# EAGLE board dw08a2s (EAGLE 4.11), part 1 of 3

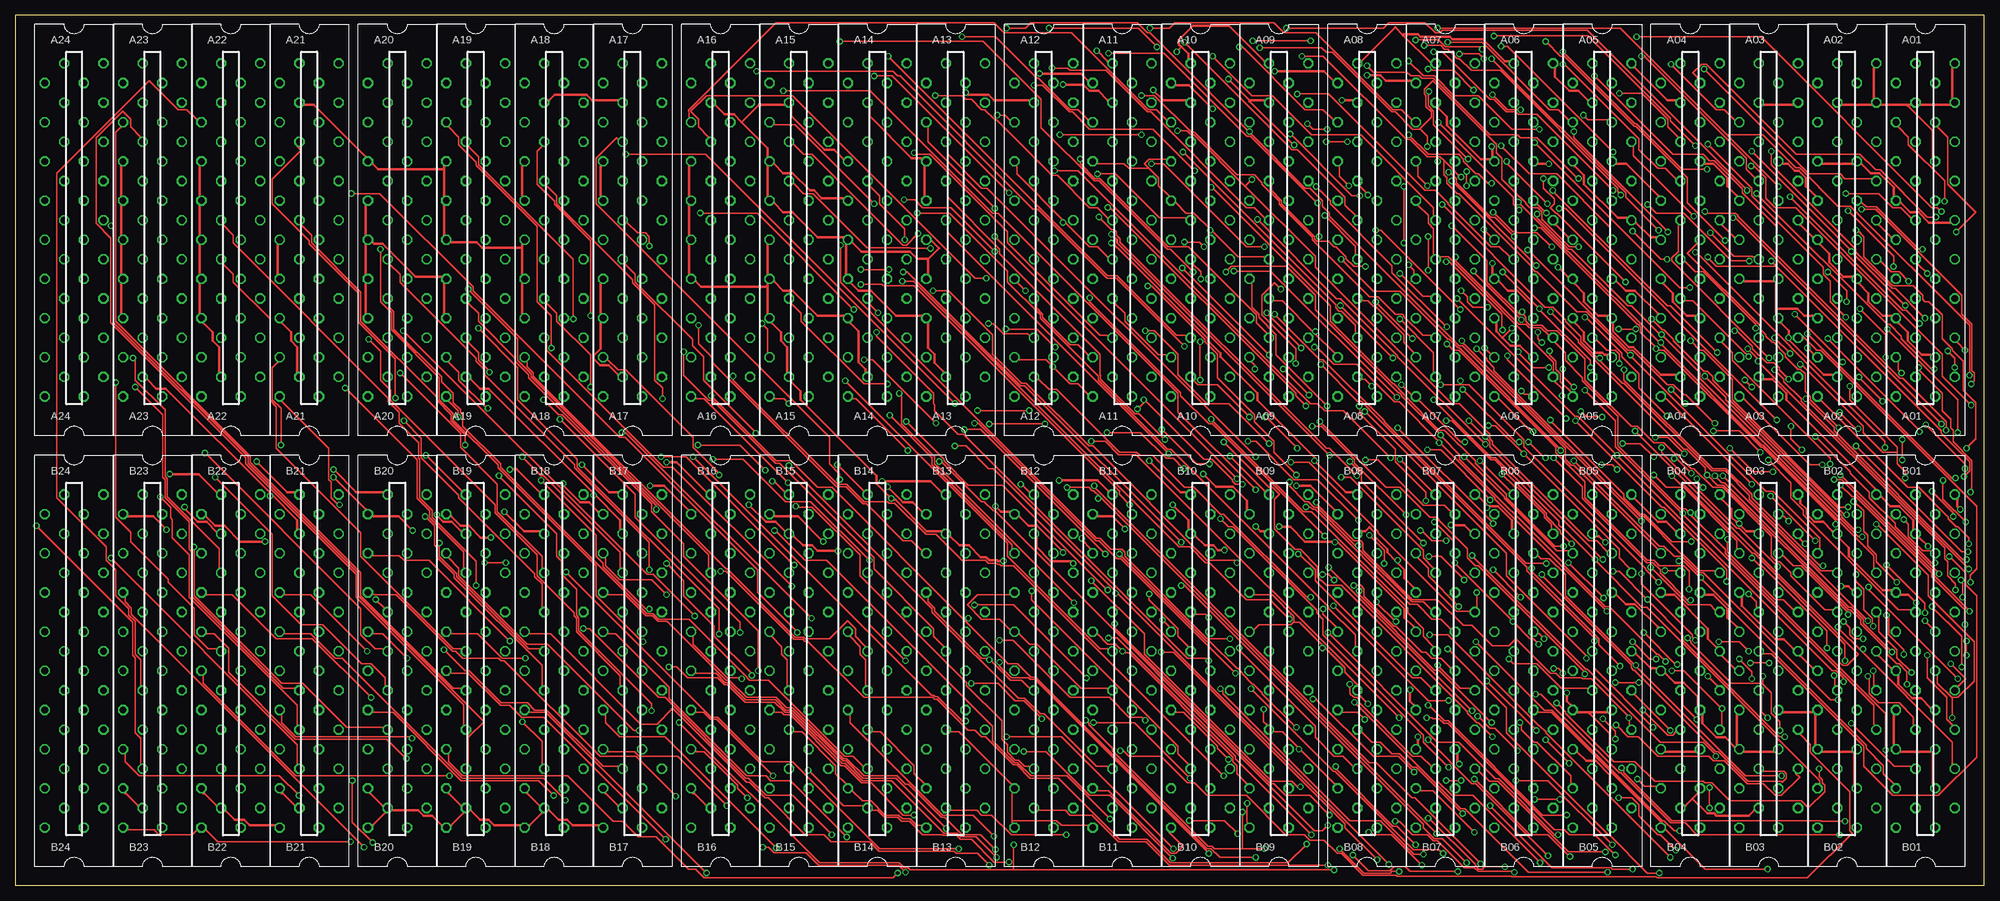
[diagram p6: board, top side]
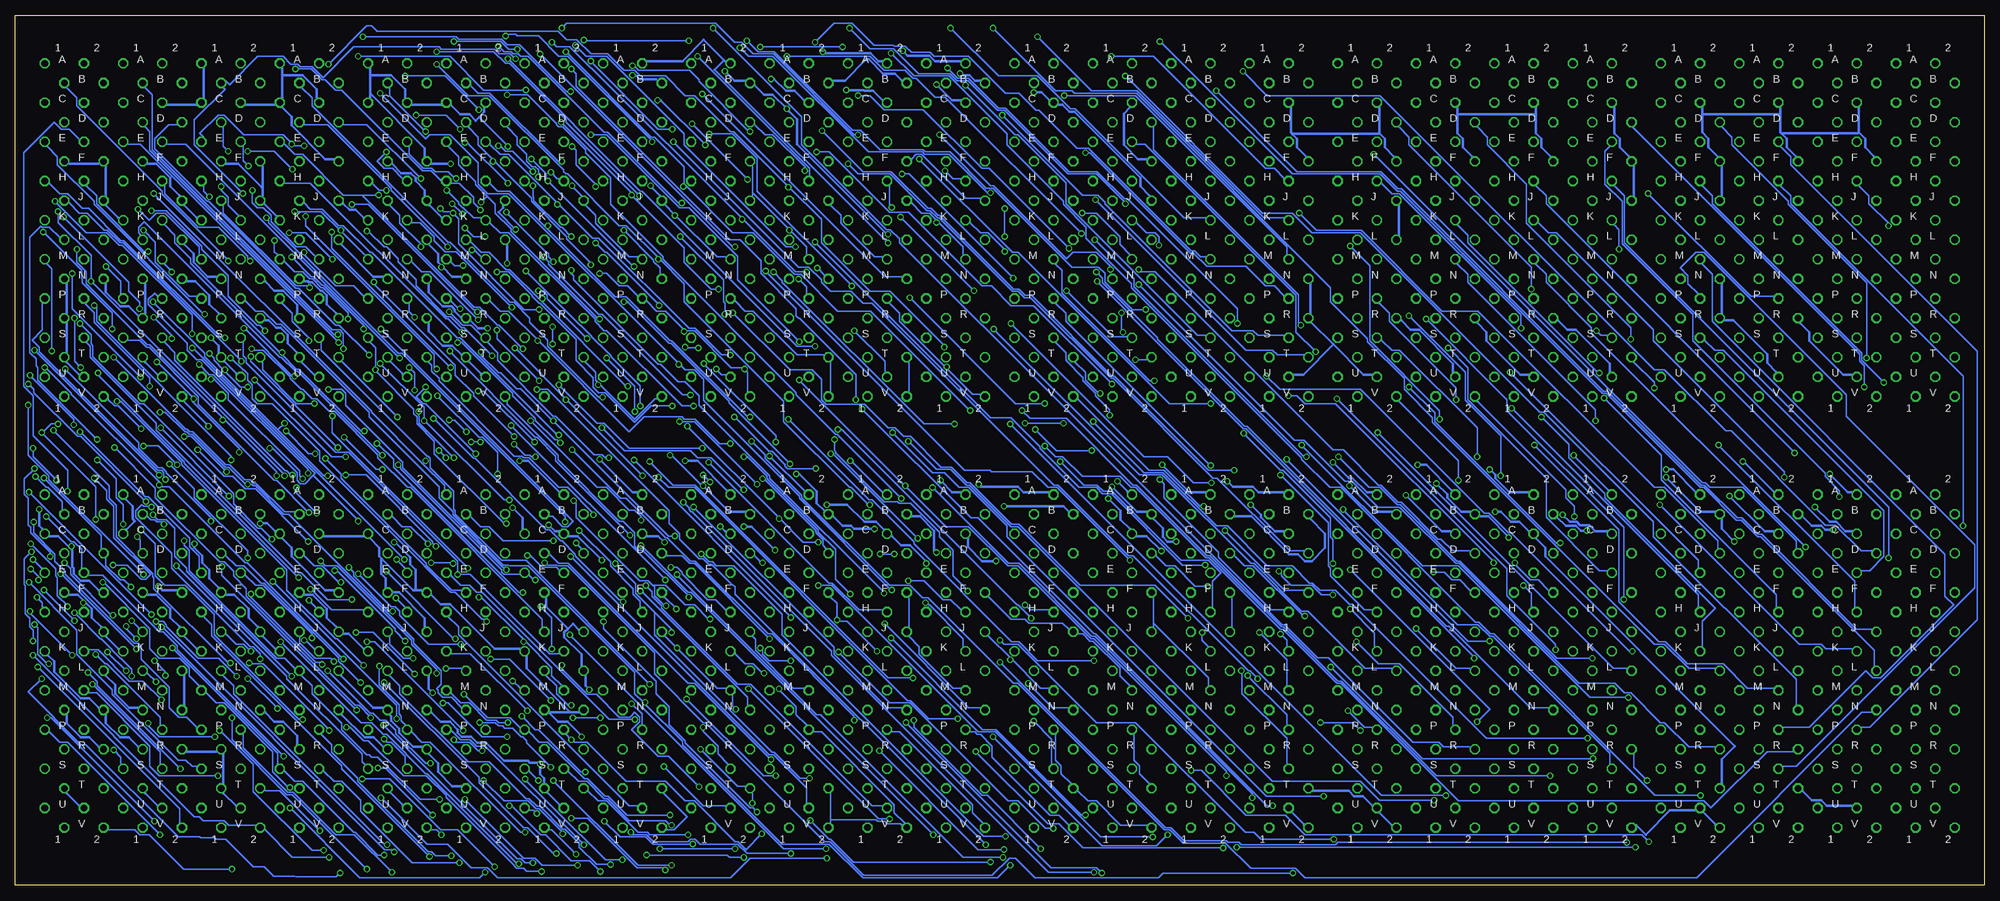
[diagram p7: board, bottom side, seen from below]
Size 319.07 x 140.96 mm. Coordinates in mm from the lower left corner, seen from the top.
Outline: 319.07,140.96 0,140.96 0,0 319.07,0 319.07,140.96
Copper layers (1*16): Top 0.035mm / dielectric 1.5mm / Bottom 0.035mm
Design rules "8mils": minimum track width 8mil, minimum drill 24mil, track to track 6mil, track to pad 8mil, pad to pad 8mil, via to via 6mil, smd to smd 8mil, copper to edge 40mil, drill to drill 10mil, minimum pad ring 10mil, minimum via ring 8mil, stop-mask expansion 0mil, vias tented up to drill 0mil, thermal gap 10mil
Net classes: 1 supply: width 0.381 mm

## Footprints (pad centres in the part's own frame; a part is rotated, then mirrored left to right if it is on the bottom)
H807 = drill 1.092 octagon: A1 4.763,28.575; A2 -1.587,28.575; B1 1.587,25.4; B2 -4.763,25.4; C1 4.763,22.225; C2 -1.587,22.225; D1 1.587,19.05; D2 -4.763,19.05; E1 4.763,15.875; E2 -1.587,15.875; F1 1.587,12.7; F2 -4.763,12.7; H1 4.763,9.525; H2 -1.587,9.525; J1 1.587,6.35; J2 -4.763,6.35; K1 4.763,3.175; K2 -1.587,3.175; L1 1.587,0; L2 -4.763,0; M1 4.763,-3.175; M2 -1.587,-3.175; N1 1.587,-6.35; N2 -4.763,-6.35; P1 4.763,-9.525; P2 -1.587,-9.525; R1 1.587,-12.7; R2 -4.763,-12.7; S1 4.763,-15.875; S2 -1.587,-15.875; T1 1.587,-19.05; T2 -4.763,-19.05; U1 4.763,-22.225; U2 -1.587,-22.225; V1 1.587,-25.4; V2 -4.763,-25.4

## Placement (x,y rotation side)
A01  M903  [H807]  309.55,104.61 0 top
A02  M903  [H807]  296.85,104.61 0 top
A03  M903  [H807]  284.15,104.61 0 top
A04  M903  [H807]  271.45,104.61 0 top
A05  M903  [H807]  257.16,104.61 0 top
A06  M907  [H807]  244.46,104.61 0 top
A07  M651  [H807]  231.76,104.61 0 top
A08  M651  [H807]  219.06,104.61 0 top
A09  M651  [H807]  204.77,104.61 0 top
A10  M651  [H807]  192.07,104.61 0 top
A11  M651  [H807]  179.37,104.61 0 top
A12  M651  [H807]  166.67,104.61 0 top
A13  W011  [H807]  152.39,104.61 0 top
A14  W011  [H807]  139.69,104.61 0 top
A15  W011  [H807]  126.98,104.61 0 top
A16  W011  [H807]  114.28,104.61 0 top
A17  W011  [H807]  100,104.61 0 top
A18  W011  [H807]  87.3,104.61 0 top
A19  W011  [H807]  74.6,104.61 0 top
A20  W011  [H807]  61.9,104.61 0 top
A21  W011  [H807]  47.61,104.61 0 top
A22  W011  [H807]  34.91,104.61 0 top
A23  W011  [H807]  22.21,104.61 0 top
A24  H807  [H807]  9.51,104.61 0 top
B01  M903  [H807]  309.55,34.76 0 top
B02  M903  [H807]  296.85,34.76 0 top
B03  M903  [H807]  284.15,34.76 0 top
B04  M903  [H807]  271.45,34.76 0 top
B05  M903  [H807]  257.16,34.76 0 top
B06  M101  [H807]  244.46,34.76 0 top
B07  M907  [H807]  231.76,34.76 0 top
B08  M651  [H807]  219.06,34.76 0 top
B09  M651  [H807]  204.77,34.76 0 top
B10  M651  [H807]  192.07,34.76 0 top
B11  M651  [H807]  179.37,34.76 0 top
B12  M651  [H807]  166.67,34.76 0 top
B13  M651  [H807]  152.39,34.76 0 top
B14  M651  [H807]  139.69,34.76 0 top
B15  M651  [H807]  126.98,34.76 0 top
B16  M517  [H807]  114.28,34.76 0 top
B17  M517  [H807]  100,34.76 0 top
B18  M517  [H807]  87.3,34.76 0 top
B19  M517  [H807]  74.6,34.76 0 top
B20  M517  [H807]  61.9,34.76 0 top
B21  M517  [H807]  47.61,34.76 0 top
B22  M517  [H807]  34.91,34.76 0 top
B23  M517  [H807]  22.21,34.76 0 top
B24  H807  [H807]  9.51,34.76 0 top

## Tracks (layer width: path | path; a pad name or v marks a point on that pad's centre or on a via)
-15V  (via drill 0.61)
  Top 0.381: v24.5,57.62 22.34,59.78 18.15,59.78 B23.B2 | v40.5,55.72 36.43,55.72 33.89,58.26 32.37,58.26 30.85,59.78 B22.B2 | v64.37,57.49 62.09,59.78 57.9,59.78 B20.B2 56.75,60.92 v51.55,66.13 | v77.07,56.35 75.42,56.35 73.52,58.26 72.12,58.26 70.6,59.78 B19.B2 | v102.86,64.73 105.14,64.73 109.08,60.8 B16.B2 | v88.76,65.11 88.76,64.86 91.55,62.06 92.95,62.06 94.47,60.54 B17.B2 | v165.97,131.53 172.71,131.53 173.85,130.39 A11.B2 | v204.07,131.92 212.08,131.92 213.6,130.39 A08.B2 | v219.06,131.28 221.22,131.28 222.11,130.39 226.3,130.39 A07.B2 | v194.04,125.82 190.23,129.63 188.07,129.63 A10.B2 | v207.63,64.73 209.92,64.73 213.85,60.8 B08.B2 | v179.82,57.75 177.79,59.78 175.37,59.78 B11.B2 | v141.34,64.6 143.88,62.06 145.4,62.06 146.92,60.54 B13.B2 | v158.86,61.43 159.75,60.54 161.15,60.54 B12.B2 162.67,59.78 164.2,58.26 165.59,58.26 169.78,54.06 v169.78,53.94 | v192.52,66.64 194.55,64.6 197.34,64.6 199.63,62.32 199.63,60.92 B09.B2 | v177.66,105.5 178.55,104.61 178.55,104.1 v212.96,69.68 | v130.92,55.72 126.86,59.78 122.92,59.78 B15.B2
  Bottom 0.381: v24.5,57.62 25.77,57.62 26.4,58.26 27.93,58.26 29.45,59.78 B22.B2 | v40.5,55.72 42.53,57.75 42.53,59.4 B21.B2 43.55,60.54 45.96,60.54 v51.55,66.13 | v64.37,57.49 65.39,57.49 66.15,58.26 67.8,58.26 69.2,59.65 B19.B2 | v77.07,56.35 77.07,56.48 80.38,59.78 81.77,59.78 B18.B2 83.3,60.54 84.69,60.54 86.98,62.83 86.98,63.34 v88.76,65.11 | v102.86,64.73 98.66,60.54 96,60.54 B17.B2 | B15.B2 121.52,59.78 118.73,59.78 112.63,53.68 111.24,53.68 110.09,52.54 108.95,52.54 106.79,54.7 106.79,56.98 109.2,59.4 B16.B2 | v165.97,131.53 165.72,131.28 164.45,131.28 163.56,130.39 162.67,130.39 A12.B2 | A10.B2 186.55,130.39 184.64,130.39 181.21,133.82 180.71,133.82 178.42,131.53 176.52,131.53 175.37,130.39 A11.B2 | v204.07,131.92 202.55,130.39 200.77,130.39 A09.B2 199.25,129.63 197.72,128.11 196.33,128.11 v194.04,125.82 193.79,125.44 193.66,125.44 192.39,124.17 192.39,120.1 177.79,105.5 v177.66,105.5 | v219.06,131.28 218.55,131.28 217.92,130.65 215.25,130.65 215,130.39 A08.B2 | B09.B2 200.77,60.54 203.44,60.54 v207.63,64.73 208.01,64.99 212.71,69.68 v212.96,69.68 | v179.82,57.75 183.12,57.75 183.63,58.26 185.02,58.26 186.55,59.78 B10.B2 187.95,60.67 189.22,61.94 189.22,63.84 192.01,66.64 v192.52,66.64 | v141.34,64.6 137.27,60.54 135.62,60.54 B14.B2 134.61,59.4 133.08,57.87 133.08,56.48 132.32,55.72 v130.92,55.72 | v158.86,61.43 149.21,61.43 148.32,60.54 B13.B2 | v169.78,53.94 170.17,54.32 170.17,57.49 172.45,59.78 173.85,59.78 B11.B2
A06U1  (via drill 0.61)
  Top 0.203: v240.9,66.64 243.06,64.48 243.44,64.48 247.76,60.16 247.76,59.65 248.91,58.51 248.91,57.75 B06.C1 | v250.68,79.34 250.68,80.48 249.54,81.62 A06.U1 249.29,83.15 249.29,84.8 232.27,101.82 230.87,101.82 A07.M2 229.86,102.2 229.86,106.39 228.97,107.28 228.97,108.55 227.32,110.2 A07.J2 | v192.14,98.26 192.14,99.4 190.87,100.67 A10.M2 | v228.84,113.37 227.32,114.9 227.32,116.55 A07.F2 | v216.14,113.37 214.62,114.9 214.62,116.55 A08.F2 | 169.97,107.59 174.1,103.47 175.37,103.47 177.02,101.82 A11.M2 | 169.97,107.59 162.29,115.28 162.29,116.55 A12.F2 | 183.69,116.23 185.28,114.64 185.28,113.37 186.93,111.72 A10.J2 188.07,110.58 189.72,108.93 190.99,108.93 193.72,106.2 | 183.69,116.23 182.99,116.93 183.75,117.69 186.55,117.69 A10.F2 | A11.F2 175.37,116.93 179.69,116.93 180.45,116.17 183.63,116.17 183.69,116.23 | v169.78,107.4 169.97,107.59 | 193.72,106.2 198.11,101.82 202.42,101.82 A09.M2 | v212.2,108.55 217.16,103.59 217.16,102.2 A08.M2 | 193.72,106.2 v193.66,106.13
  Bottom 0.203: v240.9,66.64 240.9,70.19 243.32,72.61 243.95,72.61 v250.68,79.34 | v192.14,98.26 190.87,96.99 190.87,95.85 A10.P2 | 199.63,112.23 199.63,116.55 A09.F2 | 199.63,112.23 199.63,111.72 A09.J2 | 193.6,106.2 199.63,112.23 | 193.6,106.2 190.87,103.47 190.87,102.2 A10.M2 | A08.M2 218.17,101.82 219.57,101.82 225.03,107.28 225.03,108.55 226.68,110.2 A07.J2 227.32,111.72 228.84,113.25 v228.84,113.37 | 212.14,108.61 213.85,110.32 A08.J2 214.62,111.72 216.14,113.25 v216.14,113.37 | 212.14,108.61 205.34,101.82 203.95,101.82 A09.M2 | 169.59,107.59 170.93,108.93 172.2,108.93 173.85,110.58 A11.J2 | 169.59,107.59 165.47,103.47 165.47,102.2 A12.M2 | A12.J2 162.67,111.34 165.09,111.34 172.2,118.45 173.09,118.45 173.85,117.69 A11.F2 | A11.M2 178.55,101.82 179.82,101.82 185.28,107.28 185.28,108.55 186.93,110.2 A10.J2 | 169.59,107.59 v169.78,107.4 | 212.14,108.61 v212.2,108.55 | v193.66,106.13 193.6,106.2
A06V1  (via drill 0.61)
  Top 0.203: A12.T2 162.67,85.18 166.99,85.18 v168.13,84.04 170.93,81.24 172.2,81.24 173.85,79.59 A11.V2 | A12.P2 165.47,94.32 165.47,93.56 166.48,92.54 166.48,92.04 170.93,87.59 172.2,87.59 173.85,85.94 A11.T2 | A10.T2 186.55,85.94 185.28,85.94 179.82,91.4 179.82,92.67 178.17,94.32 A11.P2 | 210.49,89.56 213.85,86.19 A08.T2 | 210.49,89.56 205.34,94.7 203.95,94.7 A09.P2 | v200.9,83.65 200.9,84.29 200.39,84.8 A09.T2 | v224.65,81.11 226.17,79.59 226.3,79.59 A07.V2 227.44,78.57 234.17,71.84 v234.94,71.84 | v244.08,80.1 244.59,79.59 245.35,79.59 A06.V1 | A08.P2 218.17,94.7 219.19,94.7 220.08,93.81 220.46,93.81 225.03,89.24 225.03,87.97 226.68,86.32 A07.T2 | v224.39,99.15 228.08,95.47 229.47,95.47 A07.P2 | 210.49,89.56 v210.68,89.75
  Bottom 0.203: A11.V2 174.23,79.97 174.23,84.8 A11.T2 | A10.V2 186.93,79.97 186.93,84.8 A10.T2 188.07,85.94 192.39,85.94 199.5,93.05 200.77,93.05 202.42,94.7 A09.P2 | 168.32,83.97 175.75,91.4 175.75,92.67 177.4,94.32 A11.P2 | 168.32,83.97 163.94,79.59 162.67,79.59 A12.V2 | v168.13,84.04 168.26,84.04 168.32,83.97 | A09.V2 200.39,79.97 200.39,83.15 v200.9,83.65 201.28,83.91 203.06,83.91 209.03,89.88 210.55,89.88 210.62,89.94 | 224.46,81.31 225.03,81.88 225.03,83.15 226.68,84.8 A07.T2 | 224.46,81.31 218.68,75.53 215.38,78.83 215,78.83 A08.V2 | 224.46,81.31 v224.65,81.11 | v244.08,80.1 243.19,80.1 v234.94,71.84 | v224.39,99.15 223.25,99.15 221.22,97.12 219.82,97.12 218.17,95.47 A08.P2 216.77,94.7 215.12,93.05 213.73,93.05 210.62,89.94 | v210.68,89.75 210.68,89.88 210.62,89.94
B07U1  (via drill 0.61)
  Top 0.203: B15.M2 125.08,32.35 125.08,36.54 124.19,37.43 124.19,38.7 122.54,40.35 B15.J2 | B14.M2 137.78,32.35 137.78,36.54 136.89,37.43 136.89,38.7 135.24,40.35 B14.J2 | B11.M2 177.02,31.97 172.71,31.97 165.59,39.08 164.32,39.08 162.67,40.73 B12.J2 161.15,41.49 159.5,43.14 156.58,43.14 154.29,45.43 155.94,47.08 161.15,47.08 B12.F2 | v185.91,43.02 186.93,42 186.93,41.87 B10.J2 | 157.91,36.6 161.28,33.24 163.05,33.24 164.32,31.97 B12.M2 | 157.91,36.6 157.72,36.79 156.58,36.79 148.96,44.41 148.96,44.92 147.94,45.94 147.94,46.7 B13.F2 | B11.J2 175.37,40.73 177.02,39.08 178.29,39.08 v179.44,37.94 179.82,37.68 180.45,37.68 197.34,20.79 197.34,20.03 197.98,19.39 197.98,18.12 199.63,16.47 B09.T2 | 157.91,36.6 v157.85,36.54 | v211.95,44.79 211.95,43.9 213.98,41.87 B08.J2 | v199.63,13.3 199.63,10.12 B09.V2 | 208.07,22.12 213.85,16.35 B08.T2 | 208.07,22.12 205.34,24.85 203.95,24.85 B09.P2 202.8,26 202.3,26.51 v202.3,28.54 | 208.07,22.12 v208.01,22.06 | 207.19,42.7 206.74,42.25 201.53,42.25 200.77,41.49 B09.J2 | 207.19,42.7 207.25,42.76 207.25,43.52 203.69,47.08 200.77,47.08 B09.F2 | v219.19,29.43 217.79,30.82 B08.M2 217.66,32.35 215.5,34.51 215.5,35.27 212.08,38.7 | v234.55,11.65 227.06,19.14 226.43,19.14 224.27,21.3 223.12,21.3 221.22,23.2 219.82,23.2 218.17,24.85 B08.P2 | 212.08,38.7 208.14,42.63 207.25,42.63 207.19,42.7 | v211.82,38.44 212.08,38.7
  Bottom 0.203: B15.F2 121.91,46.7 121.91,41.87 B15.J2 | B14.M2 138.42,32.35 140.07,34 140.07,35.27 144.38,39.59 144.89,39.59 146.04,40.73 146.92,40.73 B13.J2 148.32,41.49 149.34,42.51 154.8,42.51 155.43,43.14 157.72,43.14 161.4,46.83 B12.F2 | 134.61,42.51 134.61,41.87 B14.J2 | 134.61,42.51 134.61,46.7 B14.F2 | 134.61,42.51 125.72,33.62 125.72,32.35 B15.M2 | 157.66,36.73 161.4,40.48 B12.J2 | 157.66,36.73 152.89,31.97 151.5,31.97 B13.M2 | B10.F2 186.93,46.7 185.91,45.68 v185.91,43.02 185.53,42.76 184.26,42.76 v179.44,37.94 | B12.M2 165.85,31.97 167.12,31.97 172.58,37.43 172.58,38.7 174.23,40.35 B11.J2 174.23,41.87 174.23,46.7 B11.F2 | v157.85,36.54 157.66,36.73 | B08.J2 213.85,40.48 v211.82,38.44 205.34,31.97 203.95,31.97 B09.M2 202.8,30.82 202.8,29.05 v202.3,28.54 | v211.95,44.79 213.85,46.7 213.98,46.7 B08.F2 | v199.63,13.3 199.63,14.95 B09.T2 200.77,16.09 202.04,16.09 v208.01,22.06 | B08.V2 213.6,8.98 212.33,8.98 210.17,11.14 213.98,14.95 B08.T2 | B10.M2 191.25,31.97 193.03,31.97 199.12,38.06 199.12,39.84 199.63,40.35 B09.J2 | v219.19,29.43 217.54,27.78 217.54,26 B08.P2 | v234.55,11.65 235.06,12.15 235.82,12.15 B07.U1
B07V1  (via drill 0.61)
  Top 0.203: B13.V2 146.92,9.74 146.04,9.74 145.02,10.76 143.75,10.76 143.11,11.39 140.96,11.39 138.67,13.68 137.27,13.68 135.62,15.33 B14.T2 134.61,16.47 132.95,18.12 132.95,19.39 127.49,24.85 126.1,24.85 B15.P2 | B11.T2 175.37,15.33 177.15,15.33 187.31,5.17 188.07,5.17 189.22,6.31 186.93,8.6 B10.V2 | 161.53,10.5 161.53,14.95 B12.T2 161.4,16.35 152.89,24.85 151.5,24.85 B13.P2 | 161.53,10.5 161.53,10.12 B12.V2 | 161.53,10.5 168.77,10.5 169.53,9.74 173.85,9.74 B11.V2 | v228.2,5.04 226.68,5.04 221.22,10.5 216.27,10.5 195.69,31.08 195.69,31.46 v195.31,31.84 | B14.P2 138.8,24.85 140.19,24.85 145.65,19.39 145.65,18.12 147.31,16.47 B13.T2
  Bottom 0.203: B14.P2 137.78,24.47 137.78,20.28 136.89,19.39 136.89,18.12 135.24,16.47 B14.T2 | B12.P2 164.32,24.85 163.56,24.85 163.18,24.47 162.67,24.47 160.77,22.57 160.77,20.79 151.37,11.39 149.97,11.39 148.32,9.74 B13.V2 | B14.V2 135.62,9.74 139.94,9.74 143.88,13.68 145.27,13.68 146.92,15.33 B13.T2 147.94,16.47 149.59,18.12 149.59,19.39 150.48,20.28 150.48,24.47 B13.P2 | 186.93,10.63 186.93,10.12 B10.V2 | 186.93,10.63 186.93,14.95 B10.T2 | B11.P2 177.02,24.85 175.75,24.85 163.94,13.04 163.94,11.77 162.29,10.12 B12.V2 | v228.2,5.04 232.14,8.98 232.65,8.98 B07.V1 | v195.31,31.84 195.31,31.71 192.52,28.92 192.52,27.65 190.87,26 B10.P2 189.72,24.85 188.45,24.85 176.64,13.04 176.64,11.77 174.99,10.12 B11.V2 175.37,9.74 175.63,10 177.79,10 178.17,10.38 179.31,10.38 179.56,10.63 186.93,10.63
GND  (via drill 0.61)
  Top 0.381: A04.R1 272.27,92.29 270.88,92.29 268.59,94.58 268.59,95.97 267.07,97.5 A04.N2 | A03.N2 280.15,97.88 284.97,97.88 A03.N1 285.35,97.5 285.35,93.43 | 285.35,93.43 285.35,92.67 A03.R1 286.12,91.15 287.39,89.88 v287.39,88.73 287.51,88.35 293.1,82.77 294.5,82.77 A02.U2 | A02.R2 291.32,92.29 289.93,92.29 288.78,93.43 285.35,93.43 | A01.L2 304.02,104.99 301.99,107.02 A02.K1 | A01.K1 313.55,107.4 310.12,107.4 308.47,109.05 307.07,109.05 305.55,110.58 A01.J2 304.4,111.72 304.4,113.12 302.12,115.4 300.72,115.4 299.2,116.93 A02.F1 297.67,116.93 292.85,116.93 A02.F2 | A03.L2 278.62,104.99 276.59,107.02 A04.K1 | A04.F1 273.8,116.93 275.19,116.93 277.48,114.64 277.48,113.25 279,111.72 A03.J2 | A03.K1 289.29,107.02 291.32,104.99 A02.L2 292.47,103.85 293.99,102.32 293.99,100.93 296.28,98.64 297.67,98.64 A02.N1 298.82,97.5 300.34,95.97 300.34,94.58 302.63,92.29 304.02,92.29 A01.R2 305.17,91.15 306.69,89.62 306.69,88.23 308.98,85.94 310.37,85.94 A01.T1 | A03.F1 286.5,116.93 287.26,116.93 288.4,115.79 289.04,115.79 290.18,114.64 290.18,113.25 291.7,111.72 A02.J2 | 241.03,88.73 242.3,87.46 243.83,87.46 245.35,85.94 A06.T1 | 241.03,88.73 240.02,89.75 240.02,91.15 A06.R2 | A05.T1 258.05,85.94 257.54,85.94 257.16,86.32 256.14,86.32 254.24,88.23 254.24,89.62 252.72,91.15 A05.R2 | A06.R1 245.73,92.67 245.73,94.07 243.44,96.35 241.92,96.35 240.4,97.88 A06.N2 239.38,99.02 v239.38,100.8 | v237.98,106.26 239.13,105.12 A06.L2 | A04.U2 269.1,82.77 266.69,82.77 262.24,87.21 261.48,87.21 258.94,89.75 258.94,91.15 A05.R1 258.05,92.29 256.53,92.29 254.24,94.58 254.24,95.97 252.72,97.5 A05.N2 251.7,98.64 251.57,98.64 v250.05,100.16
  Top 0.381: v242.56,90.26 241.03,88.73 | A04.R2 266.18,92.54 266.18,92.67 262.49,96.35 260.97,96.35 259.45,97.88 A05.N1 | A06.K1 249.54,107.02 249.67,107.02 251.7,104.99 A05.L2 | A04.L2 265.92,104.99 265.03,104.99 262.62,107.4 A05.K1 261.22,108.17 259.7,108.17 254.24,113.63 254.24,115.02 252.72,116.55 A05.F2 | A05.F1 259.45,116.93 261.1,116.93 266.3,111.72 A04.J2 | A07.C2 230.49,126.07 232.01,124.55 232.01,123.15 237.48,117.69 239,117.69 A06.F2 239.38,118.07 239.38,119.6 v239.25,119.72 | A06.A1 249.54,132.42 249.54,131.03 251.83,128.74 253.35,128.74 254.87,127.22 A05.C2 | v248.52,116.93 246.75,116.93 A06.F1 | A04.C2 269.1,127.22 267.7,127.22 262.37,132.55 A05.A1 | A03.C1 288.15,126.45 283.32,126.45 A03.C2 | A02.C1 300.85,126.45 296.02,126.45 A02.C2 | 306.69,126.45 302.37,126.45 A02.C1 | 306.69,126.45 307.2,126.45 A01.C2 308.72,126.45 313.55,126.45 A01.C1 313.93,127.6 313.93,132.42 A01.A1 | A02.A1 301.23,132.42 301.23,127.6 A02.C1 | A01.F1 310.75,118.07 310.75,122.26 306.69,126.33 306.69,126.45 | B03.A1 289.29,62.57 289.29,61.94 290.31,60.92 290.31,60.16 291.58,58.89 292.97,58.89 294.5,57.37 B02.C2 295.64,56.22 297.17,54.7 297.17,53.3 302.63,47.84 304.02,47.84 B01.F2 305.55,47.08 306.82,47.08 v308.09,45.81 | v315.2,60.92 314.69,61.43 314.69,62.57 B01.A1 | v309.99,54.95 308.6,56.35 308.47,56.35 B01.C2 307.58,57.75 307.58,59.14 305.29,61.43 303.9,61.43 302.37,62.95 B02.A1 301.61,64.1 287,78.7 287,79.72 284.72,82 283.32,82 A03.U2 | B02.K1 301.99,37.17 304.02,35.14 B01.L2 305.17,34 305.17,32.6 307.45,30.32 308.85,30.32 310.37,28.79 B01.N1 | B01.N2 304.4,27.65 304.4,22.82 B01.R2 305.55,21.68 310.37,21.68 B01.R1 310.75,21.3 310.75,16.47 B01.T1
  Top 0.381: v232.65,58.38 234.81,58.38 235.82,57.37 B07.C1 | 238.75,61.43 240.27,61.43 242.56,59.14 242.56,57.75 B06.C2 | 238.75,61.43 237.22,62.95 B07.A1 | v238.49,61.18 238.75,61.43 | 223.76,52.54 225.16,51.14 225.16,49.75 226.68,48.22 B07.F2 | 223.76,52.54 222.36,53.94 222.36,54.45 220.33,56.48 220.33,57.11 219.44,58 218.81,57.37 218.17,57.37 B08.C2 | v204.84,58.13 206.61,58.13 209.03,55.72 213.85,55.72 | 213.85,55.72 214.23,55.72 225.16,44.79 225.16,43.4 226.68,41.87 B07.J2 | 213.85,55.72 v213.85,55.59 | v224.01,52.67 223.89,52.67 223.76,52.54 | v295.9,48.48 297.04,48.48 297.67,47.84 B02.F1 | B03.F2 279.77,46.7 279.77,45.3 285.23,39.84 286.62,39.84 288.15,38.32 B03.K1 289.29,37.17 291.32,35.14 B02.L2 | B04.R2 267.45,21.68 272.27,21.68 B04.R1 | B03.R2 278.62,22.44 277.1,23.96 275.7,23.96 273.42,26.25 273.42,27.65 B04.N1 272.65,29.17 272.65,30.57 270.37,32.86 268.97,32.86 267.45,34.38 B04.L2 265.92,35.14 265.03,35.14 262.62,37.55 B05.K1 | B03.N2 279,27.65 279,22.82 B03.R2 | B02.T1 298.05,16.47 298.05,21.3 B02.R1 297.67,21.68 292.85,21.68 B02.R2 291.7,22.82 291.7,27.65 B02.N2 291.32,28.03 286.5,28.03 B03.N1 | 271.76,14.06 272.65,14.95 B04.T1 | 271.76,14.06 270.62,12.92 B04.U2 | 271.76,14.06 274.18,11.65 275.32,11.65 275.7,11.27 280.91,11.27 281.8,12.15 B03.U2 | B03.R2 280.15,21.68 284.97,21.68 B03.R1 | B05.T1 258.43,16.47 258.43,17.87 256.14,20.16 254.62,20.16 253.1,21.68 B05.R2 | v234.05,19.65 233.67,20.03 233.67,21.3 B07.R1 | 255.13,28.03 258.05,28.03 B05.N1 | 255.13,28.03 253.1,28.03 B05.N2 252.08,29.17 251.45,29.81 v251.45,31.2 | B05.R1 258.43,22.82 258.43,24.6 255.13,27.9 255.13,28.03
  Top 0.381: 279.32,58.57 279,58.89 278.88,58.89 278.12,59.65 278.12,61.05 276.59,62.57 B04.A1 | 279.32,58.57 280.53,57.37 281.8,57.37 B03.C2 | v279.38,58.64 279.32,58.57 | B03.L2 278.62,35.14 276.59,37.17 B04.K1 275.7,38.57 274.31,39.97 274.31,41.62 268.84,47.08 267.45,47.08 B04.F2 | v290.05,55.33 289.29,56.1 289.29,56.22 B03.C1 | B04.F1 273.8,47.08 275.19,47.08 277.48,44.79 277.48,43.4 279,41.87 B03.J2 | v227.32,24.09 227.32,22.82 B07.R2 | v257.67,55.59 256.65,56.6 256.27,56.6 B05.C2 | B05.A1 262.37,62.7 266.18,58.89 267.57,58.89 269.1,57.37 B04.C2 | B04.J2 266.18,41.74 266.18,41.87 262.49,45.55 260.97,45.55 259.45,47.08 B05.F1 | v226.05,31.71 226.05,29.81 226.68,29.17 B07.N2 | v169.78,129.76 173.09,129.76 174.1,128.74 175.5,128.74 177.02,127.22 A11.C2 | v184.39,128.87 186.04,127.22 189.72,127.22 A10.C2 | 200.01,127.22 202.42,127.22 A09.C2 | v196.58,130.65 200.01,127.22 | v215,127.22 216.77,127.22 A08.C2 | v207.25,119.98 207.12,119.98 200.01,127.09 200.01,127.22 | A13.U2 150.48,83.15 148.96,84.67 148.96,86.07 147.94,87.08 147.94,91.15 A13.R2 146.92,92.29 142.73,92.29 138.67,96.35 136.64,96.35 135.37,97.62 A14.N2 134.61,99.02 134.61,103.85 A14.L2 | 147.94,101.43 147.94,99.02 A13.N2 | 147.94,101.43 149.72,103.21 148.32,104.61 A13.L2 | A15.F2 121.91,116.55 121.91,111.72 A15.J2 122.92,110.58 124.44,109.05 125.97,109.05 130.03,104.99 134.22,104.99 A14.L2 | A14.J2 134.22,111.34 130.67,111.34 129.4,112.61 128.76,112.61 125.97,115.4 124.44,115.4 122.92,116.93 A15.F2 | 147.94,101.43 147.81,101.56 146.16,101.56 145.02,102.7 137.15,102.7 135.62,104.23 A14.L2 | v154.04,128.49 154.42,128.11 157.72,128.11 158.61,127.22 164.32,127.22 A12.C2
  Top 0.381: v171.44,52.16 171.05,52.54 167.75,52.54 165.47,54.83 165.47,56.22 B12.C2 | v187.56,61.68 190.1,59.14 190.1,57.75 B10.C2 191.25,56.6 192.77,55.08 194.17,55.08 194.93,54.32 v195.95,54.32 | v118.86,61.68 121.65,58.89 123.17,58.89 124.7,57.37 B15.C2 126.1,56.6 127.62,55.08 129.14,55.08 130.03,54.19 v133.34,54.19 | v160.13,52.54 159.24,52.54 159.12,52.67 157.85,52.67 157.34,53.18 156.45,53.18 154.54,55.08 153.02,55.08 151.5,56.6 B13.C2 150.1,57.37 147.69,57.37 142.61,62.45 142.23,62.45 v141.97,62.7 141.59,62.95 141.59,63.08 139.56,65.11 139.56,66.38 127.24,78.7 127.24,80.1 125.72,81.62 A15.U2 125.08,83.15 125.08,87.21 124.06,88.23 124.06,89.62 122.54,91.15 A15.R2 121.91,92.67 121.91,96.99 | A14.F2 134.22,117.69 132.7,119.21 131.18,119.21 125.72,124.68 125.72,126.07 A15.C2 124.7,126.45 120.51,126.45 117.71,123.66 | A14.C2 138.42,126.07 138.42,124.68 145.27,117.82 146.8,117.82 146.92,117.69 A13.F2 147.31,116.55 147.31,111.72 A13.J2 | A14.U2 137.78,83.15 137.78,83.65 136.64,84.8 136.64,89.75 135.24,91.15 A14.R2 134.22,92.29 130.03,92.29 125.97,96.35 124.44,96.35 122.92,97.88 A15.N2 | 121.91,96.99 121.91,97.5 A15.N2 | A15.L2 121.91,103.85 121.91,99.02 A15.N2 | A17.F2 94.85,116.55 94.85,111.72 A17.J2 | A17.N2 94.85,97.5 94.85,92.67 A17.R2 94.85,91.15 94.85,86.96 93.71,85.81 93.71,85.31 94.73,84.29 96.12,84.29 97.65,82.77 A17.U2 | A16.F2 109.2,116.55 109.2,111.72 A16.J2 109.2,110.2 109.2,105.37 A16.L2 109.2,103.85 109.2,99.02 A16.N2 110.22,97.88 111.11,96.99 121.91,96.99 | 117.71,123.66 116.44,124.93 114.92,124.93 113.4,126.45 A16.C2
  Top 0.381: A15.F2 121.91,118.07 121.91,119.47 117.71,123.66 | B21.T2 43.16,14.95 43.29,14.95 45.32,12.92 B21.U2 | B23.T2 17.77,14.95 17.89,14.95 19.92,12.92 B23.U2 | B22.T2 30.46,14.95 30.59,14.95 32.62,12.92 B22.U2 34.02,12.15 35.55,10.63 37.07,10.63 37.96,9.74 42.15,9.74 B21.V2 | B16.T2 109.84,14.95 109.97,14.95 112,12.92 B16.U2 | B17.T2 95.62,14.95 97.65,12.92 B17.U2 | B18.U2 85.33,11.77 83.3,9.74 B18.V2 81.77,9.74 77.58,9.74 76.69,10.63 75.3,10.63 73.77,12.15 B19.U2 | B18.T2 82.92,14.95 84.95,12.92 B18.U2 | B20.V2 57.9,9.74 59.93,11.77 B20.U2 | B20.T2 57.52,14.95 59.55,12.92 B20.U2 | B19.U2 72.63,11.77 70.6,9.74 B19.V2 69.07,9.74 67.55,11.27 66.15,11.27 65.26,12.15 61.07,12.15 B20.U2 | B19.T2 70.22,14.95 72.25,12.92 B19.U2 | B17.V2 94.47,9.74 90.28,9.74 89.39,10.63 88,10.63 86.47,12.15 B18.U2 | v27.42,61.3 27.42,61.05 29.58,58.89 30.97,58.89 32.62,57.24 B22.C2 | 41.51,63.34 24.37,80.48 22.84,80.48 21.32,82 A23.U2 | 41.51,63.34 45.7,59.14 45.7,57.75 B21.C2 | 41.51,63.34 v41.26,63.08 | A23.R2 17.13,92.67 17.13,97.5 A23.N2 17.13,99.02 17.13,103.85 A23.L2 17.13,105.37 17.13,110.2 A23.J2 17.13,111.72 17.13,116.55 A23.F2 | A21.U2 45.7,83.15 45.7,87.21 44.69,88.23 44.69,89.62 43.16,91.15 A21.R2 | A21.L2 42.53,103.85 42.53,99.02 A21.N2 | A22.U2 33.01,83.15 33.01,87.21 31.99,88.23 31.99,89.62 30.46,91.15 A22.R2 29.83,92.67 29.83,97.5 A22.N2 29.83,99.02 29.83,103.85 A22.L2 29.83,105.37 29.83,110.2 A22.J2 29.83,111.72 29.83,116.55 A22.F2 | A18.J2 82.15,111.72 82.15,116.55 A18.F2 | 69.45,116.04 69.45,111.72 A19.J2 69.45,110.2 69.45,105.37 A19.L2 70.6,104.23 74.79,104.23 75.68,103.34 82.15,103.34
  Top 0.381: 69.45,116.04 69.45,116.55 A19.F2 | A19.R2 69.45,92.67 69.45,97.5 A19.N2 69.07,98.64 64.88,98.64 59.55,103.97 58.15,103.97 57.9,104.23 A20.L2 | A20.R2 56.75,92.67 56.75,97.5 A20.N2 56.75,99.02 56.75,103.85 A20.L2 | A20.J2 56.75,110.2 56.75,105.37 A20.L2 | 69.45,116.04 58.79,116.04 57.9,116.93 A20.F2 56.75,118.07 48.37,126.45 46.72,126.45 A21.C2 | v68.31,60.03 68.31,59.91 69.33,58.89 70.72,58.89 72.25,57.37 B19.C2 | v79.23,60.54 82.41,57.37 84.95,57.37 B18.C2 | A18.R2 82.15,92.67 82.15,97.5 A18.N2 82.15,99.02 82.15,103.34 | 82.15,103.34 82.15,103.85 A18.L2 | 93.84,63.34 76.69,80.48 75.3,80.48 73.77,82 A19.U2 | 93.84,63.34 98.03,59.14 98.03,57.75 B17.C2 | 93.84,63.34 v93.71,63.21 | A17.C2 97.65,127.22 93.46,127.22 92.57,128.11 87.36,128.11 86.47,127.22 A18.C2 | v201.03,58.13 201.79,57.37 202.42,57.37 B09.C2
  Bottom 0.381: A02.U2 296.02,82.77 298.05,84.8 A02.T1 | A03.U2 283.19,82.89 285.23,84.92 A03.T1 286.12,86.32 286.12,87.46 v287.39,88.73 | A02.N2 291.32,97.88 289.93,97.88 287.64,95.59 287.64,94.2 286.12,92.67 A03.R1 | A04.R1 273.42,92.67 273.42,94.07 275.7,96.35 277.1,96.35 278.62,97.88 A03.N2 | A02.K1 302.37,108.17 304.4,110.2 A01.J2 304.4,111.72 304.4,116.55 A01.F2 305.55,116.93 310.37,116.93 A01.F1 | A04.K1 276.72,108.42 278.75,110.45 A03.J2 279,111.72 279,113.12 | 279,113.12 279,116.55 A03.F2 | A03.F1 284.97,116.93 282.94,116.93 279.13,113.12 279,113.12 | A01.U2 308.72,82.77 310.75,84.8 A01.T1 310.75,86.32 310.75,91.15 A01.R1 310.75,92.67 310.75,97.5 A01.N1 | A02.N1 298.05,97.5 298.05,92.67 A02.R1 299.2,92.29 300.72,93.81 302.12,93.81 304.4,96.1 304.4,97.5 A01.N2 | A03.K1 289.67,108.17 291.7,110.2 A02.J2 292.47,111.72 293.99,113.25 293.99,114.64 296.28,116.93 297.67,116.93 A02.F1 | A03.N1 286.5,98.64 287.89,98.64 290.18,100.93 290.18,102.32 291.7,103.85 A02.L2 | A05.U2 256.27,82.77 256.27,82.89 258.3,84.92 A05.T1 | A06.U2 243.57,82.77 243.57,82.89 245.6,84.92 A06.T1 246.75,85.94 248.27,87.46 249.79,87.46 252.08,89.75 252.08,91.15 A05.R2 | A04.U2 270.62,82.77 272.65,84.8 A04.T1 273.42,86.32 274.94,87.85 274.94,89.24 276.08,90.39 276.85,90.39 277.99,91.53 278.62,91.53 A03.R2 | v239.38,100.8 239.38,103.85 A06.L2 | v237.98,106.26 240.78,109.05 240.02,109.82 240.02,110.2 A06.J2 | A05.N2 252.08,97.5 252.08,96.1 249.79,93.81 248.4,93.81 247.89,93.31 247.89,93.05 246.75,91.91 A06.R1 245.35,91.53 244.08,90.26 v242.56,90.26 | A04.N1 272.27,97.88 271.64,97.88 271.51,97.75 271,97.75 269.61,96.35 269.35,96.35 268.59,95.59 268.59,94.2 267.07,92.67 A04.R2
  Bottom 0.381: 249.92,100.29 250.56,100.93 250.56,102.32 252.08,103.85 A05.L2 | 249.92,100.29 248.27,98.64 246.75,98.64 A06.N1 | A06.K1 249.92,108.17 251.95,110.2 252.08,110.2 A05.J2 252.72,111.72 252.72,112.61 254.24,114.13 254.24,114.64 255,115.4 256.53,115.4 258.05,116.93 A05.F1 | A04.J2 266.05,110.45 265.92,110.45 264.91,109.44 263.89,109.44 262.62,108.17 A05.K1 | A05.N1 259.45,98.64 261.1,98.64 266.3,103.85 A04.L2 | 243.95,124.42 244.46,123.91 245.48,124.93 247,124.93 248.52,126.45 A06.C1 249.92,126.45 254.87,126.45 A05.C2 255.89,127.6 255.89,128.99 258.18,131.28 261.61,131.28 | 243.95,124.42 243.06,125.31 243.06,126.07 A06.C2 | 243.95,124.42 v239.25,119.72 | v248.52,116.93 251.7,116.93 A05.F2 252.72,118.07 252.72,119.47 261.48,128.23 261.61,128.23 | 261.61,131.28 261.61,132.42 A05.A1 | 261.61,131.28 261.61,128.23 | 261.61,128.23 261.61,127.6 A05.C1 | A04.F2 267.45,117.69 268.84,117.69 274.31,123.15 274.31,124.55 275.83,126.07 A04.C1 | A03.C2 281.8,126.45 276.97,126.45 A04.C1 | A02.C2 294.5,126.45 289.67,126.45 A03.C1 288.53,127.6 288.53,132.42 A03.A1 | 275.83,131.28 275.83,127.6 A04.C1 | 275.83,131.28 275.83,132.42 A04.A1 | A04.C2 270.24,127.6 270.24,128.99 272.53,131.28 275.83,131.28 | 249.92,100.29 v250.05,100.16 | B02.C1 301.1,57.62 299.71,59.02 300.09,59.4 300.09,61.43 301.23,62.57 B02.A1 | 310.25,54.7 309.87,54.32 309.87,51.65 309.61,51.4 309.61,50.51 308.47,49.37 307.07,49.37 305.55,47.84 B01.F2 | 310.25,54.7 312.15,56.6 313.55,56.6 B01.C1 314.69,57.75 315.2,58.26 v315.2,60.92 | 310.25,54.7 v309.99,54.95 | B02.N1 299.2,28.79 300.59,28.79 302.88,31.08 302.88,32.47 304.4,34 B01.L2
  Bottom 0.381: B02.K1 302.37,38.32 304.4,40.35 B01.J2 305.17,41.87 306.69,43.4 306.69,44.79 307.83,45.94 | 307.83,45.94 308.98,47.08 310.37,47.08 B01.F1 | B01.U2 308.72,12.92 310.75,14.95 B01.T1 | B01.N1 310.75,27.65 310.75,26.25 308.47,23.96 307.07,23.96 305.55,22.44 B01.R2 | B01.K1 313.8,37.3 312.79,36.28 312.79,34.63 308.47,30.32 307.07,30.32 305.55,28.79 B01.N2 304.4,27.65 304.4,26.25 302.12,23.96 300.72,23.96 299.2,22.44 B02.R1 | v308.09,45.81 307.96,45.81 307.83,45.94 | v232.65,58.38 231.63,57.37 230.87,57.37 B07.C2 229.47,56.6 227.95,56.6 v224.01,52.67 | v238.49,61.18 236.84,59.52 236.84,57.75 B07.C1 | v204.84,58.13 204.07,57.37 203.95,57.37 B09.C2 | 229.47,41.62 228.71,42.38 227.7,41.36 B07.J2 | 229.47,41.62 230.11,40.98 230.11,40.22 227.32,37.43 227.32,35.52 B07.L2 226.68,34 226.68,32.35 v226.05,31.71 | B07.F1 233.03,46.7 233.03,45.17 229.47,41.62 | v213.85,55.59 214.87,56.6 216.77,56.6 B08.C2 | v295.9,48.48 295.26,47.84 292.85,47.84 B02.F2 | B03.K1 289.67,38.32 291.7,40.35 B02.J2 292.47,41.87 293.99,43.4 293.99,44.79 296.28,47.08 297.67,47.08 B02.F1 | B04.R1 273.42,22.82 273.42,24.22 275.7,26.51 277.1,26.51 278.62,28.03 B03.N2 | B02.U2 296.02,12.92 298.05,14.95 B02.T1 | B03.U2 283.32,12.92 285.35,14.95 B03.T1 285.35,16.47 285.35,21.3 B03.R1 286.5,21.68 291.32,21.68 B02.R2 | B02.L2 291.7,34 291.7,29.17 B02.N2 | B05.U2 256.27,12.92 256.27,13.04 258.3,15.08 B05.T1 | B06.T1 246.75,16.09 248.27,16.09 250.56,18.38 250.56,19.77 252.08,21.3 B05.R2 253.1,22.44 254.62,22.44 256.91,24.73 256.91,25.36 258.18,26.63 258.18,27.39 258.43,27.65 B05.N1 259.45,28.79 261.1,28.79 266.3,34 B04.L2
  Bottom 0.381: B07.U2 230.87,12.92 230.87,13.04 232.9,15.08 B07.T1 233.41,16.47 233.41,17.36 234.05,18 v234.05,19.65 234.43,19.9 235.7,19.9 235.95,20.16 239.89,20.16 242.81,23.08 244.21,23.08 245.22,24.09 246.75,24.09 247.38,24.73 247.38,25.23 248.65,26.51 250.18,26.51 251.7,28.03 B05.N2 | B04.N2 266.3,27.65 266.18,27.65 262.49,23.96 260.97,23.96 259.45,22.44 B05.R1 | v251.45,31.2 252.08,31.84 252.08,34 B05.L2 | B04.F2 267.45,47.84 268.84,47.84 274.31,53.3 274.31,54.7 275.83,56.22 B04.C1 276.97,57.37 278.24,58.64 v279.38,58.64 | B05.K1 262.62,38.32 265.03,40.73 265.92,40.73 B04.J2 267.07,41.87 268.59,43.4 268.59,44.79 270.88,47.08 272.27,47.08 B04.F1 | B04.K1 276.97,38.32 279,40.35 B03.J2 279.77,41.87 281.29,43.4 281.29,44.79 283.58,47.08 284.97,47.08 B03.F1 286.12,48.22 287.64,49.75 287.64,51.14 288.78,52.29 288.78,53.43 290.05,54.7 v290.05,55.33 | v227.32,24.09 227.32,24.22 229.6,26.51 231.12,26.51 232.52,27.9 | 232.52,27.9 232.65,28.03 B07.N1 | 229.22,28.03 232.4,28.03 232.52,27.9 | 229.22,28.03 227.7,28.03 B07.N2 | 229.22,28.03 229.22,28.16 236.21,35.14 236.21,37.17 B07.K1 237.22,38.32 241.41,38.32 248.65,45.55 250.18,45.55 251.7,47.08 B05.F2 253.1,47.84 254.24,47.84 | B05.J2 252.72,41.87 252.72,43.27 256.91,47.46 B05.F1 259.06,48.22 259.06,49.75 259.83,50.51 259.83,52.79 259.7,52.92 | 254.24,47.84 254.62,47.84 259.7,52.92 | 259.7,52.92 260.08,53.3 260.08,54.7 261.61,56.22 B05.C1 262.62,56.6 269.1,56.6 B04.C2 | v257.67,55.59 257.54,55.59 255.13,53.18 255.13,52.03 254.24,51.14 254.24,47.84 | v169.78,129.76 167.24,127.22 165.85,127.22 A12.C2
  Bottom 0.381: v184.39,128.87 181.6,128.87 181.47,128.74 180.07,128.74 178.55,127.22 A11.C2 | v196.58,130.65 196.07,130.65 194.17,128.74 192.77,128.74 191.25,127.22 A10.C2 | v215,127.22 214.49,127.22 v207.25,119.98 | A14.J2 135.24,111.72 136.76,113.25 136.76,114.64 147.43,125.31 148.19,125.31 149.34,126.45 150.1,126.45 A13.C2 151.5,127.22 152.77,128.49 v154.04,128.49 | v171.44,52.16 171.44,52.41 174.1,55.08 175.5,55.08 177.02,56.6 B11.C2 178.29,57.62 179.56,58.89 181.47,58.89 184.26,61.68 v187.56,61.68 | v118.86,61.68 117.21,60.03 117.21,59.65 114.92,57.37 113.4,57.37 B16.C2 | v133.34,54.19 135.75,56.6 137.4,56.6 B14.C2 138.42,57.75 139.94,59.27 139.94,60.67 v141.97,62.7 | v160.13,52.54 162.42,52.54 164.7,54.83 164.7,56.22 B12.C2 | A14.F2 135.62,117.69 137.15,117.69 139.43,119.98 139.43,125.06 138.42,126.07 A14.C2 | A17.L2 94.85,105.37 94.85,110.2 A17.J2 | 98.03,121.88 98.03,126.07 A17.C2 | 98.03,121.88 97.14,120.99 97.14,119.6 95.62,118.07 A17.F2 | A18.U2 86.09,83.15 86.09,84.54 91.55,90 92.95,90 94.47,91.53 A17.R2 | 105.46,87.65 109.08,91.27 A16.R2 109.2,92.67 109.2,97.5 A16.N2 | 105.46,87.65 100.57,82.77 99.17,82.77 A17.U2 | A16.U2 112,82.77 110.35,82.77 105.46,87.65 | 112,121.63 111.36,120.99 111.36,119.6 109.84,118.07 A16.F2 | 112,121.63 112.38,122.01 112.38,126.07 A16.C2 | 98.03,121.88 98.16,121.75 111.87,121.75 112,121.63 | B21.V2 43.55,9.74 43.55,9.87 45.58,11.9 B21.U2 46.72,12.15 50.91,12.15 54.85,8.22 56.37,9.74 B20.V2 | B23.U2 21.32,12.92 25.51,12.92 26.4,13.81 27.93,13.81 29.45,15.33 B22.T2 | B16.V2 110.22,9.74 110.22,9.87 112.25,11.9 B16.U2
  Bottom 0.381: B17.V2 96,9.74 98.03,11.77 B17.U2 99.17,12.92 100.7,14.44 102.09,14.44 102.98,15.33 108.82,15.33 B16.T2 | v27.42,61.3 25,58.89 23.99,58.89 22.46,57.37 21.32,57.37 B23.C2 | v41.26,63.08 35.55,57.37 34.02,57.37 B22.C2 | 20.3,122.01 20.3,126.07 A23.C2 | 20.3,122.01 19.29,120.99 19.29,119.6 17.77,118.07 A23.F2 | A21.N2 42.53,97.5 42.53,92.67 A21.R2 42.15,91.53 40.62,91.53 35.16,86.07 35.16,84.67 33.64,83.15 A22.U2 | A21.J2 42.53,111.72 42.53,116.55 A21.F2 43.16,118.07 44.69,119.6 44.69,120.99 45.7,122.01 45.7,124.93 | 45.7,124.93 45.7,126.07 A21.C2 | 33.01,124.93 33.01,122.01 32.75,121.75 | 33.01,124.93 33.01,126.07 A22.C2 | 32.75,121.75 31.99,120.99 31.99,119.6 30.46,118.07 A22.F2 | 45.7,124.93 33.01,124.93 | 20.3,122.01 20.43,121.88 32.62,121.88 32.75,121.75 | A23.U2 21.32,82.77 22.84,82.77 28.31,88.23 28.31,89.62 29.83,91.15 A22.R2 | 85.33,124.93 85.33,121.88 84.44,120.99 84.44,119.6 82.92,118.07 A18.F2 | 85.33,124.93 85.33,126.07 A18.C2 | 72.63,124.93 72.63,121.88 71.74,120.99 71.74,119.6 70.22,118.07 A19.F2 | 72.63,124.93 72.63,126.07 A19.C2 | 85.33,124.93 72.63,124.93 | A20.U2 60.69,83.15 60.69,84.54 66.15,90 67.55,90 69.07,91.53 A19.R2 | A20.J2 56.75,111.72 56.75,116.55 A20.F2 57.52,118.07 59.04,119.6 59.04,120.99 59.93,121.88 59.93,126.07 A20.C2 | v68.31,60.03 67.17,58.89 66.03,58.89 65.52,58.38 63.99,58.38 62.98,57.37 61.07,57.37 B20.C2 | v79.23,60.54 78.34,60.54 76.69,58.89 75.3,58.89 73.77,57.37 B19.C2 72.63,56.22 71.11,54.7 71.11,53.3 40.37,22.57 42.53,20.41 42.53,16.47 B21.T2 | A19.U2 73.77,82.77 75.17,82.77 80.63,88.23 80.63,89.62 82.15,91.15 A18.R2
  Bottom 0.381: v93.71,63.21 87.87,57.37 86.47,57.37 B18.C2 | v201.03,58.13 199.76,58.13 v195.95,54.32
I_3CYCLE  (via drill 0.61)
  Top 0.203: v265.42,25.62 255.89,35.14 255.89,37.17 B05.K2 | v233.79,2.25 226.05,2.25 225.28,3.01 223.38,3.01 222.74,2.38 219.31,2.38 v216.77,4.92 | v201.03,4.53 195.18,4.53 193.79,5.93 193.15,5.93 165.34,33.74 164.58,33.74 162.42,35.9 160.89,35.9 153.97,42.82 | 153.97,42.82 132.32,64.48 130.03,64.48 125.72,68.8 123.3,68.8 v112.76,79.34 | v79.49,52.29 v76.06,52.29 | v238.62,93.69 236.21,93.69 235.32,94.58 235.32,95.34 v234.3,96.35 | v220.46,94.58 v226.43,88.61 | v193.53,68.29 191.37,68.29 v185.79,73.88 | v154.42,43.27 153.97,42.82
  Bottom 0.203: v265.42,25.62 264.78,25.62 262.62,23.46 261.86,23.46 256.14,17.74 252.46,17.74 249.29,14.57 249.29,14.31 238.24,3.26 238.24,3.14 237.86,2.76 236.71,2.76 236.21,2.25 v233.79,2.25 | v216.77,4.92 203.69,4.92 203.31,4.53 v201.03,4.53 | v112.76,79.34 111.36,79.34 110.09,78.07 105.14,78.07 79.49,52.41 v79.49,52.29 | v76.06,52.29 76.06,52.03 73.52,49.49 72.25,49.49 70.6,47.84 B19.F2 | v238.62,93.69 247.64,102.7 249.41,102.7 251.19,104.48 251.19,105.12 253.48,107.4 254.87,107.4 A05.K2 | v234.3,96.35 233.67,96.35 232.9,95.59 232.9,95.08 v226.43,88.61 | v220.46,94.58 219.82,94.58 213.09,87.85 212.84,87.85 203.44,78.45 203.44,78.19 v193.53,68.29 | v185.79,73.88 185.15,73.88 156.7,45.43 156.58,45.43 v154.42,43.27
I_AC00  (via drill 0.61)
  Top 0.203: v184.14,116.93 186.04,116.93 199.5,103.47 v202.42,103.47 | v234.05,134.71 237.22,134.71 v237.98,133.95 | v287.39,59.02 286.62,59.78 286.5,59.78 B03.B1 | v311.01,83.65 310.63,83.65 305.67,88.61 305.67,88.99 303.77,90.89 303.39,90.89 v282.18,112.1
  Bottom 0.203: v184.14,116.93 182.48,115.28 177.28,115.28 171.31,109.31 170.8,109.31 169.66,108.17 169.4,108.17 157.47,96.23 156.58,96.23 155.56,95.21 154.54,95.21 141.46,82.13 141.08,82.13 124.95,66 124.32,66 112.51,54.19 110.22,54.19 B16.D2 | v202.42,103.47 202.8,103.47 v234.05,134.71 | v237.98,133.95 238.11,133.95 238.87,134.71 240.65,134.71 241.41,135.47 250.05,135.47 250.43,135.85 264.27,135.85 269.23,130.9 271,132.68 272.91,132.68 273.29,133.06 274.43,133.06 275.7,134.33 279.77,134.33 284.34,129.76 284.97,130.39 A03.B1 285.35,129.25 285.1,128.99 290.05,124.04 290.05,119.98 v282.18,112.1 | v287.39,59.02 287.39,59.65 294.62,66.89 294.62,67.02 295.26,67.65 295.9,67.65 299.07,70.83 299.07,71.72 v311.01,83.65
I_AC01  (via drill 0.61)
  Top 0.203: v123.05,57.49 123.17,57.49 128,52.67 131.43,52.67 158.35,25.74 158.35,23.46 161.91,19.9 162.42,19.9 164.58,17.74 170.42,17.74 v177.4,10.76 | v200.26,31.84 213.6,18.5 213.85,18.5 226.55,5.8 230.74,5.8 v231.38,5.17 | v259.32,32.86 v263.13,32.86 | v284.59,118.96 284.59,116.8 298.31,103.09 298.31,102.58 304.15,96.74 304.66,96.74 v309.48,91.91 | v308.47,83.91 308.47,83.53 312.28,79.72 312.28,76.92 313.68,75.53 313.68,74.13 314.06,73.75 314.06,71.84 317.1,68.8 317.1,63.97 v316.85,63.72 | v297.04,43.9 297.04,44.16 289.42,51.78 288.15,51.78 286.5,53.43 B03.D1
  Bottom 0.203: v123.05,57.49 113.4,47.84 110.22,47.84 B16.F2 | v177.4,10.76 179.18,10.76 v200.26,31.84 | v231.38,5.17 231.89,5.17 236.08,9.36 236.71,9.36 243.95,16.6 243.95,17.49 v259.32,32.86 | v263.13,32.86 266.18,35.9 266.3,35.9 266.69,36.28 266.69,36.92 278.75,48.98 279.26,48.98 282.05,51.78 283.32,51.78 284.97,53.43 B03.D1 | v284.59,118.96 285.35,119.72 285.35,122.9 A03.D1 | v309.48,91.91 309.48,84.92 v308.47,83.91 | v297.04,43.9 v316.85,63.72
I_AC02  (via drill 0.61)
  Top 0.203: v117.71,33.49 117.59,33.62 115.3,33.62 109.84,39.08 109.84,40.35 B16.J2 | v212.46,120.48 v215.89,120.48 | v239.63,137.63 254.87,137.63 268.21,124.29 268.21,123.91 v272.27,119.85 | v308.6,73.49 308.6,73.75 v293.74,88.61 | v296.66,92.04 294.12,94.58 294.12,97.88 292.97,99.02 292.97,100.16 281.42,111.72 281.42,112.99 v274.31,120.1
  Bottom 0.203: v117.71,33.49 118.98,34.76 119.24,34.76 137.91,53.43 138.67,53.43 150.1,64.86 150.73,64.86 180.2,94.32 181.72,94.32 183.63,96.23 186.93,96.23 188.45,97.75 188.45,98.13 190.49,100.16 192.14,100.16 v212.46,120.48 | v215.89,120.48 215.89,120.61 229.6,134.33 231,134.33 234.3,137.63 237.73,137.63 237.98,137.88 239.38,137.88 v239.63,137.63 | v272.27,119.85 273.92,119.85 274.24,120.17 | 274.24,120.17 275.7,121.63 282.05,121.63 285.23,124.8 286.24,124.8 289.16,121.88 288.53,121.25 A03.E1 | v308.6,73.49 298.05,62.95 297.55,62.95 290.81,56.22 290.81,54.83 289.29,53.3 289.29,51.4 B03.E1 | v293.74,88.61 293.74,89.12 v296.66,92.04 | 274.24,120.17 v274.31,120.1
I_AC03  (via drill 0.61)
  Top 0.203: v150.86,9.23 142.73,17.36 137.4,17.36 134.61,20.16 134.1,20.16 125.84,28.41 124.83,28.41 123.17,30.06 118.35,30.06 115.55,32.86 115.05,32.86 113.52,34.38 110.22,34.38 B16.L2 | v185.66,37.81 187.69,37.81 215.5,10 215.5,9.36 v220.71,4.15 | v236.46,17.23 245.48,8.22 248.4,8.22 v251.95,4.66 | v287.64,111.59 287.64,111.47 305.93,93.18 306.44,93.18 v308.6,91.02 | v277.48,56.1 277.48,54.06 285.23,46.32 286.5,46.32 288.15,44.67 B03.H1
  Bottom 0.203: v150.86,9.23 152.13,9.23 156.58,13.68 158.23,13.68 174.1,29.55 177.4,29.55 v185.66,37.81 | v220.71,4.15 223.38,4.15 227.44,8.22 227.57,8.22 236.46,17.11 v236.46,17.23 | v251.95,4.66 266.18,18.89 266.18,19.39 287.26,40.48 287.26,42.25 288.53,43.52 B03.H1 | v287.64,111.59 288.53,112.48 288.53,113.37 A03.H1 | v308.6,91.02 306.82,89.24 306.82,87.72 306.56,87.46 306.56,85.69 298.94,78.07 298.31,78.07 283.7,63.46 283.7,61.81 279.77,57.87 279.26,57.87 v277.48,56.1
I_AC04  (via drill 0.61)
  Top 0.203: v122.79,17.74 113.65,26.89 112.63,26.89 111.49,28.03 110.22,28.03 B16.N2 | v174.86,64.73 174.86,64.48 219.44,19.9 220.58,19.9 226.3,14.19 226.81,14.19 v237.48,3.52 | v276.08,39.46 279.38,39.46 v280.91,37.94 | v271.38,96.86 269.73,96.86 v246.24,120.36 | v239.25,113.75 238.62,113.75 237.09,115.28 236.71,115.28 234.68,117.31 234.68,117.69 233.92,118.45 228.97,118.45 v225.79,121.63 | v192.01,81.88 v192.01,88.1
  Bottom 0.203: v122.79,17.74 122.79,18.5 144.26,39.97 144.77,39.97 156.58,51.78 158.23,51.78 164.58,58.13 168.26,58.13 v174.86,64.73 175.25,64.99 192.01,81.75 v192.01,81.88 | v237.48,3.52 237.73,3.52 252.33,18.12 252.59,18.12 258.94,24.47 259.45,24.47 261.35,26.38 263,26.38 v276.08,39.46 | v280.91,37.94 282.05,39.08 283.32,39.08 284.97,40.73 B03.J1 | v271.38,96.86 271.64,97.12 273.54,97.12 285.35,108.93 285.35,110.2 A03.J1 | v246.24,120.36 245.86,120.36 v239.25,113.75 | v225.79,121.63 223.25,121.63 211.44,109.82 209.92,109.82 202.04,101.94 202.04,98.13 v192.01,88.1
I_AC05  (via drill 0.61)
  Top 0.203: v118.6,14.19 117.08,15.71 117.08,16.22 111.62,21.68 110.22,21.68 B16.R2 | v170.42,64.48 173.98,64.48 174.48,63.97 174.74,63.97 175.75,62.95 | v230.36,8.34 175.75,62.95 | v243.19,16.98 248.4,16.98 v258.81,6.57 | v255.89,131.15 268.59,118.45 273.54,118.45 274.56,117.44 275.32,117.44 279.89,112.86 279.89,112.23 285.35,106.77 285.35,105.37 A03.L1 | v243.95,125.69 241.79,125.69 v239.38,128.11 | 175.75,62.95 v175.5,62.7
  Bottom 0.203: v118.6,14.19 118.6,14.82 144.13,40.35 144.64,40.35 156.45,52.16 158.1,52.16 v170.42,64.48 | v230.36,8.34 230.36,8.6 234.17,12.41 234.68,12.41 235.95,13.68 239.89,13.68 v243.19,16.98 | v258.81,6.57 259.19,6.57 283.7,31.08 283.7,32.35 285.35,34 B03.L1 | v255.89,131.15 249.41,131.15 v243.95,125.69 | v239.38,128.11 236.08,128.11 231.38,123.41 231.38,123.28 231,122.9 230.36,122.9 226.68,119.21 226.68,118.71 222.62,114.64 222.62,110.32 214.11,101.82 214.11,101.43 192.52,79.84 192.52,79.46 186.17,73.11 185.91,73.11 v175.5,62.7
I_AC06  (via drill 0.61)
  Top 0.203: v105.52,47.08 103.11,49.49 97.9,49.49 95.62,51.78 95.62,53.05 B17.D2 | v114.28,50.89 115.17,50.89 126.22,39.84 127.62,39.84 127.87,39.59 128.38,39.59 137.53,30.44 148.7,30.44 148.96,30.19 149.34,30.19 154.42,25.11 155.56,25.11 156.58,24.09 157.21,24.09 161.78,19.52 162.29,19.52 164.45,17.36 169.02,17.36 178.93,7.46 183.37,7.46 187.18,3.65 206.23,3.65 v209.28,6.69 | v223.63,10.38 224.27,10.38 226.43,8.22 228.84,8.22 229.86,7.2 230.49,7.2 234.81,2.88 236.46,2.88 237.09,2.25 242.81,2.25 v242.94,2.12 | v274.56,12.54 v274.56,15.84 | v299.2,109.56 301.48,109.56 315.45,95.59 315.45,92.54 317.1,90.89 317.1,83.4 317.49,83.02 317.49,81.75 v316.98,81.24 | v297.93,62.19 298.05,62.19 299.58,60.67 299.58,57.37 300.21,56.73 300.21,54.95 301.61,53.56 301.61,52.41 v304.91,49.11
  Bottom 0.203: v105.52,47.08 107.43,47.08 108.95,48.6 112.38,48.6 113.9,50.13 113.9,50.51 v114.28,50.89 | v209.28,6.69 215.76,6.69 216.9,7.84 221.09,7.84 v223.63,10.38 | v242.94,2.12 243.83,1.23 263.26,1.23 v274.56,12.54 | v274.56,15.84 274.81,15.84 277.35,18.38 277.35,21.68 285.23,29.55 286.5,29.55 288.15,31.2 B03.M1 289.29,32.35 290.94,34 290.94,35.27 292.47,36.79 295.77,36.79 297.29,38.32 297.29,41.62 304.79,49.11 v304.91,49.11 | v299.2,109.56 297.42,107.78 296.28,108.93 294.75,108.93 289.29,103.47 289.29,102.2 A03.M1 | v316.98,81.24 316.09,80.35 316.09,79.84 308.98,72.73 308.47,72.73 v297.93,62.19
I_AC07  (via drill 0.61)
  Top 0.203: v158.86,5.8 156.45,8.22 153.4,8.22 150.61,11.01 150.1,11.01 144.77,16.35 144.26,16.35 142.86,17.74 137.53,17.74 134.73,20.54 134.22,20.54 125.97,28.79 124.95,28.79 123.3,30.44 118.48,30.44 115.68,33.24 115.17,33.24 105.65,42.76 104.12,42.76 103.24,43.65 102.22,43.65 98.79,47.08 96,47.08 B17.F2 | v179.06,21.81 179.56,21.81 180.45,20.92 185.66,20.92 189.98,16.6 191.12,16.6 193.15,14.57 199.5,14.57 205.85,8.22 208.9,8.22 209.79,7.33 212.08,7.33 214.23,5.17 214.87,5.17 218.43,1.61 223.76,1.61 223.89,1.49 242.43,1.49 242.56,1.36 265.92,1.36 266.05,1.23 290.43,1.23 297.67,8.47 297.29,8.85 297.29,15.2 290.94,21.55 290.94,22.82 289.29,24.47 B03.P1 | v298.31,106.13 298.56,106.13 299.58,105.12 299.58,101.82 304.28,97.12 307.58,97.12 309.1,95.59 309.1,94.96 309.48,94.58 310.12,94.58 312.28,92.42 312.28,88.61 313.93,86.96 313.93,86.7 315.71,84.92 315.71,80.23 317.74,78.19 317.74,72.35 v316.22,70.83 | v312.41,65.62 312.41,62.57 v316.09,58.89
  Bottom 0.203: v158.86,5.8 163.05,5.8 v179.06,21.81 | v298.31,106.13 296.4,104.23 296.4,100.93 290.94,95.47 289.67,95.47 A03.P1 | v316.22,70.83 316.22,69.43 v312.41,65.62 | v316.09,58.89 316.09,57.11 312.66,53.68 312.66,52.54 311.01,50.89 311.01,50.38 299.83,39.2 299.2,39.2 298.69,38.7 298.69,36.66 294.12,32.09 294.12,28.79 292.59,27.27 291.32,27.27 289.67,25.62 B03.P1
I_AC08  (via drill 0.61)
  Top 0.203: v316.85,49.11 316.85,50.25 317.87,51.27 317.87,61.43 292.59,86.7 291.96,86.7 289.67,88.99 A03.S1 | v134.73,7.84 125.59,16.98 122.41,16.98 121.65,17.74 118.48,17.74 105.9,30.32 105.9,32.09 97.27,40.73 96,40.73 B17.J2 | v188.96,48.6 189.47,48.6 228.2,9.87 228.2,9.36 229.98,7.58 231.25,7.58 v235.19,3.65 | v259.45,26 261.35,24.09 263,24.09 266.18,20.92 274.43,20.92 275.19,20.16 276.97,20.16 280.66,16.47 283.32,16.47 285.23,14.57 286.24,14.57 289.16,17.49 288.53,18.12 B03.S1
  Bottom 0.203: v316.85,49.11 309.1,41.36 309.1,37.43 303.39,31.71 303.39,30.95 292.72,20.28 291.45,20.28 290.43,19.27 289.67,19.27 B03.S1 | v134.73,7.84 143.24,7.84 160.26,24.85 163.05,24.85 186.8,48.6 v188.96,48.6 | v235.19,3.65 236.46,3.65 237.09,4.28 237.73,4.28 v259.45,26
I_AC09  (via drill 0.61)
  Top 0.203: v160.51,90.13 165.59,90.13 v168.51,87.21 | v268.34,133.06 275.7,125.69 276.97,125.69 278.62,124.04 A03.D2 | v265.54,66.51 267.57,64.48 270.37,64.48 279,55.84 279,54.57 B03.D2 | v250.94,54.95 249.54,54.95 241.67,62.83 241.67,63.34 236.59,68.41 236.59,68.8 231.63,73.75 230.74,73.75 225.03,79.46 225.03,79.59 223.38,81.24 223.25,81.24 213.09,91.4 213.09,93.94 193.91,113.12 v193.79,113.12
  Bottom 0.203: v160.51,90.13 136.89,66.51 133.21,66.51 118.86,52.16 118.35,52.16 110.6,44.41 109.59,44.41 100.31,35.14 96,35.14 B17.L2 | v168.51,87.21 168.51,87.46 177.28,96.23 180.58,96.23 188.45,104.1 188.45,107.91 193.72,113.18 | 193.72,113.18 202.68,122.14 203.19,122.14 209.03,127.98 210.55,127.98 213.73,131.15 217.79,131.15 218.68,132.04 220.46,132.04 223.12,134.71 225.79,134.71 228.08,137 229.73,137 231.12,138.39 260.46,138.39 261.35,139.28 262.11,139.28 v268.34,133.06 | v265.54,66.51 262.24,66.51 251.45,55.72 251.45,55.46 v250.94,54.95 | 193.72,113.18 v193.79,113.12
I_AC10  (via drill 0.61)
  Top 0.203: v123.3,6.06 105.27,24.09 97.9,24.09 95.62,26.38 95.62,27.65 B17.N2 | v163.43,21.68 166.99,21.68 174.1,14.57 177.4,14.57 v187.56,4.41 | v259.83,14.19 261.99,14.19 263.13,13.04 263.13,11.27 266.18,8.22 266.56,8.22 v269.1,5.68 | v285.99,25.11 285.99,26.51 284.59,27.9 284.59,31.2 283.13,32.66 | 283.13,32.66 283.07,32.73 278.12,32.73 271.51,39.33 271.51,39.59 v271,40.09 | v281.29,116.55 281.8,116.55 283.7,114.64 283.7,111.34 285.23,109.82 288.53,109.82 312.28,86.07 312.28,82.51 v316.98,77.81 | v298.31,50.38 298.31,49.24 299.58,47.97 299.58,44.67 300.98,43.27 300.98,42.13 v301.1,42 | v299.45,39.97 297.93,39.97 297.29,40.6 297.29,41.74 v296.28,42.76 | v283.19,33.87 283.19,32.73 283.13,32.66
  Bottom 0.203: v123.3,6.06 146.04,6.06 149.97,10 151.75,10 v163.43,21.68 | v187.56,4.41 200.01,4.41 203.19,1.23 240.9,1.23 242.56,2.88 245.22,2.88 249.03,6.69 252.33,6.69 v259.83,14.19 | v269.1,5.68 271,5.68 280.53,15.2 280.53,19.65 v285.99,25.11 | v271,40.09 271,40.73 278.88,48.6 280.15,48.6 281.8,50.25 B03.E2 | v281.29,116.55 282.18,117.44 282.18,119.72 A03.E2 | v316.98,77.81 316.98,69.68 313.68,66.38 313.68,65.75 v298.31,50.38 | v301.1,42 301.1,41.62 v299.45,39.97 | v296.28,42.76 295.13,42.76 294.62,42.25 294.62,42 289.42,36.79 286.12,36.79 v283.19,33.87
I_AC11  (via drill 0.61)
  Top 0.203: v115.3,12.92 107.3,20.92 101.08,20.92 100.31,21.68 96,21.68 B17.R2 | v181.85,77.18 183.12,78.45 v182.87,78.7 183.25,78.45 192.64,69.05 193.91,69.05 197.22,65.75 197.22,65.49 197.72,64.99 v198.87,64.99 | v228.97,132.3 229.35,132.3 229.6,132.04 233.16,132.04 v236.33,128.87 | v263.51,134.33 264.02,134.33 280.53,117.82 280.53,116.04 281.93,114.64 A03.H2 | v280.91,47.21 282.18,45.94 282.18,45.05 B03.H2 | v269.35,35.78 269.1,35.78 v263.89,40.98 | v254.37,34.25 254.37,34.51 237.09,51.78 236.59,51.78 235.32,53.05 235.32,54.57 230.74,59.14 230.74,59.27 230.36,59.65 229.22,59.65 224.39,64.48 222.11,64.48 v211.44,75.15
  Bottom 0.203: v115.3,12.92 116.19,12.92 144,40.73 144.26,40.73 163.05,59.52 164.2,59.52 v181.85,77.18 | v182.87,78.7 182.87,82.77 192.01,91.91 192.14,91.91 192.52,92.29 192.52,93.43 198.23,99.15 198.23,101.18 201.66,104.61 203.31,104.61 228.2,129.5 228.2,131.53 v228.97,132.3 | v236.33,128.87 243.19,128.87 248.65,134.33 v263.51,134.33 | v280.91,47.21 280.91,46.7 270.37,36.16 269.73,36.16 v269.35,35.78 | v263.89,40.98 261.1,40.98 v254.37,34.25 | v211.44,75.15 209.03,75.15 v198.87,64.99
I_ACCEPT  (via drill 0.61)
  Top 0.203: v247.13,3.65 236.21,14.57 232.78,14.57 230.49,16.85 230.49,18.12 B07.S2 229.47,19.27 227.82,20.92 226.43,20.92 217.79,29.55 217.79,30.06 217.41,30.44 216.9,30.44 216.27,31.08 v216.27,32.6 | v149.72,68.67 150.1,68.67 156.58,62.19 156.96,62.19 158.48,60.67 158.74,60.67 210.55,8.85 211.82,8.85 v212.71,9.74
  Bottom 0.203: v247.13,3.65 254.75,3.65 263.13,12.03 263.13,13.81 266.18,16.85 267.45,16.85 269.1,18.5 B04.S2 | v149.72,68.67 145.91,64.86 143.75,64.86 142.73,63.84 141.34,63.84 130.16,52.67 125.72,52.67 123.68,50.63 125.08,49.24 125.08,45.05 B15.H2 | v212.71,9.74 212.96,9.74 213.73,10.5 219.57,10.5 223.12,14.06 223.63,14.06 226.43,16.85 227.82,16.85 229.47,18.5 B07.S2 | v216.27,32.6 236.33,52.67 240.27,52.67 247.76,60.16 247.76,60.67 248.02,60.92 248.02,63.84 251.83,67.65 251.83,69.18 252.21,69.56 252.33,69.56 269.48,86.7 269.48,87.97 A04.S2
I_ACCLR  (via drill 0.61)
  Top 0.203: v258.05,2.12 245.22,2.12 234.94,12.41 234.3,12.41 v217.03,29.68 | v157.85,3.26 155.94,5.17 152.51,5.17 152.13,5.55 139.94,5.55 138.42,7.07 132.19,7.07 131.05,8.22 128,8.22 122.03,14.19 121.52,14.19 118.98,16.73 118.48,16.73 106.54,28.66 104,26.12 101.33,26.12 86.73,40.73 83.3,40.73 B18.J2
